VERSION 5.7 ;
  DIVIDERCHAR "/" ;
  BUSBITCHARS "[]" ;
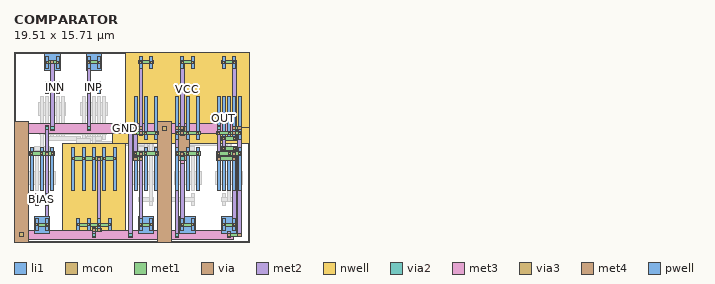
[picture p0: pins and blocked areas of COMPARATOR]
MACRO COMPARATOR
  CLASS BLOCK ;
  FOREIGN COMPARATOR ;
  ORIGIN 0.590 0.590 ;
  SIZE 19.510 BY 15.710 ;
  PIN OUT
    ANTENNADIFFAREA 0.940800 ;
    PORT
      LAYER li1 ;
        RECT 16.645 7.895 16.895 11.425 ;
        RECT 17.505 7.895 17.755 11.425 ;
        RECT 16.645 3.695 16.895 7.225 ;
        RECT 17.505 3.695 17.755 7.225 ;
      LAYER mcon ;
        RECT 16.685 7.895 16.855 8.065 ;
        RECT 17.545 7.895 17.715 8.065 ;
        RECT 16.685 7.055 16.855 7.225 ;
        RECT 17.545 7.055 17.715 7.225 ;
      LAYER met1 ;
        RECT 16.600 7.840 17.800 8.120 ;
        RECT 16.600 7.000 17.800 7.280 ;
      LAYER via ;
        RECT 16.640 7.850 16.900 8.110 ;
        RECT 16.640 7.010 16.900 7.270 ;
      LAYER met2 ;
        RECT 16.630 6.980 16.910 8.140 ;
    END
  END OUT
  PIN VCC
    ANTENNADIFFAREA 5.096000 ;
    PORT
      LAYER nwell ;
        RECT 8.600 8.840 18.920 15.120 ;
        RECT 7.550 7.560 18.920 8.840 ;
        RECT 3.440 0.000 8.600 7.560 ;
      LAYER li1 ;
        RECT 9.765 13.775 10.015 14.785 ;
        RECT 10.625 13.775 10.875 14.785 ;
        RECT 13.205 13.775 13.455 14.785 ;
        RECT 14.065 13.775 14.315 14.785 ;
        RECT 16.645 13.775 16.895 14.785 ;
        RECT 17.505 13.775 17.755 14.785 ;
        RECT 9.335 7.895 9.585 11.425 ;
        RECT 10.195 7.895 10.445 11.425 ;
        RECT 11.055 7.895 11.305 11.425 ;
        RECT 12.775 7.895 13.025 11.425 ;
        RECT 13.635 7.895 13.885 11.425 ;
        RECT 14.495 7.895 14.745 11.425 ;
        RECT 16.215 7.895 16.465 11.425 ;
        RECT 17.075 7.895 17.325 11.425 ;
        RECT 17.935 7.895 18.185 11.425 ;
        RECT 4.175 3.695 4.425 7.225 ;
        RECT 5.035 3.695 5.285 7.225 ;
        RECT 5.895 3.695 6.145 7.225 ;
        RECT 6.755 3.695 7.005 7.225 ;
        RECT 7.615 3.695 7.865 7.225 ;
        RECT 4.605 0.335 4.855 1.345 ;
        RECT 5.465 0.335 5.715 1.345 ;
        RECT 6.325 0.335 6.575 1.345 ;
        RECT 7.185 0.335 7.435 1.345 ;
      LAYER mcon ;
        RECT 9.805 14.195 9.975 14.365 ;
        RECT 10.665 14.195 10.835 14.365 ;
        RECT 13.245 14.195 13.415 14.365 ;
        RECT 14.105 14.195 14.275 14.365 ;
        RECT 16.685 14.195 16.855 14.365 ;
        RECT 17.545 14.195 17.715 14.365 ;
        RECT 9.375 8.315 9.545 8.485 ;
        RECT 10.235 8.315 10.405 8.485 ;
        RECT 11.095 8.315 11.265 8.485 ;
        RECT 12.815 8.315 12.985 8.485 ;
        RECT 13.675 8.315 13.845 8.485 ;
        RECT 14.535 8.315 14.705 8.485 ;
        RECT 16.255 8.315 16.425 8.485 ;
        RECT 17.115 8.315 17.285 8.485 ;
        RECT 17.975 8.315 18.145 8.485 ;
        RECT 4.215 6.215 4.385 6.385 ;
        RECT 5.075 6.215 5.245 6.385 ;
        RECT 5.935 6.215 6.105 6.385 ;
        RECT 6.795 6.215 6.965 6.385 ;
        RECT 7.655 6.215 7.825 6.385 ;
        RECT 4.645 0.755 4.815 0.925 ;
        RECT 5.505 0.755 5.675 0.925 ;
        RECT 6.365 0.755 6.535 0.925 ;
        RECT 7.225 0.755 7.395 0.925 ;
      LAYER met1 ;
        RECT 9.720 14.140 10.920 14.420 ;
        RECT 13.160 14.140 14.360 14.420 ;
        RECT 16.600 14.140 17.800 14.420 ;
        RECT 8.870 8.680 10.050 8.960 ;
        RECT 12.740 8.680 13.490 8.960 ;
        RECT 17.470 8.680 18.220 8.960 ;
        RECT 9.290 8.260 11.350 8.540 ;
        RECT 12.730 8.260 14.790 8.540 ;
        RECT 16.170 8.260 18.230 8.540 ;
        RECT 4.130 6.160 7.910 6.440 ;
        RECT 4.560 0.700 7.480 0.980 ;
        RECT 5.860 0.280 6.610 0.560 ;
        RECT 17.040 -0.140 18.220 0.140 ;
      LAYER via ;
        RECT 9.760 14.150 10.020 14.410 ;
        RECT 13.200 14.150 13.460 14.410 ;
        RECT 17.500 14.150 17.760 14.410 ;
        RECT 8.900 8.690 9.160 8.950 ;
        RECT 9.760 8.690 10.020 8.950 ;
        RECT 12.770 8.690 13.030 8.950 ;
        RECT 13.200 8.690 13.460 8.950 ;
        RECT 17.500 8.690 17.760 8.950 ;
        RECT 17.930 8.690 18.190 8.950 ;
        RECT 9.760 8.270 10.020 8.530 ;
        RECT 13.200 8.270 13.460 8.530 ;
        RECT 17.500 8.270 17.760 8.530 ;
        RECT 6.320 6.170 6.580 6.430 ;
        RECT 6.320 0.710 6.580 0.970 ;
        RECT 5.890 0.290 6.150 0.550 ;
        RECT 6.320 0.290 6.580 0.550 ;
        RECT 17.070 -0.130 17.330 0.130 ;
        RECT 17.930 -0.130 18.190 0.130 ;
      LAYER met2 ;
        RECT 5.880 -0.185 6.160 0.580 ;
        RECT 6.310 0.260 6.590 6.460 ;
        RECT 8.890 -0.185 9.170 8.980 ;
        RECT 9.750 8.240 10.030 14.440 ;
        RECT 12.760 -0.185 13.040 8.980 ;
        RECT 13.190 8.240 13.470 14.440 ;
        RECT 17.490 8.240 17.770 14.440 ;
        RECT 17.060 -0.185 17.340 0.240 ;
        RECT 17.920 -0.160 18.200 8.980 ;
      LAYER via2 ;
        RECT 5.880 -0.140 6.160 0.140 ;
        RECT 8.890 -0.140 9.170 0.140 ;
        RECT 12.760 -0.140 13.040 0.140 ;
        RECT 17.060 -0.140 17.340 0.140 ;
      LAYER met3 ;
        RECT -0.400 -0.400 17.600 0.400 ;
      LAYER via3 ;
        RECT -0.160 -0.160 0.160 0.160 ;
      LAYER met4 ;
        RECT -0.590 -0.590 0.590 9.410 ;
    END
  END VCC
  PIN GND
    ANTENNADIFFAREA 5.006400 ;
    PORT
      LAYER pwell ;
        RECT 1.935 13.590 3.225 14.970 ;
        RECT 5.375 13.590 6.665 14.970 ;
        RECT 1.075 0.150 2.365 1.530 ;
        RECT 9.675 0.150 10.965 1.530 ;
        RECT 13.115 0.150 14.405 1.530 ;
        RECT 16.555 0.150 17.845 1.530 ;
      LAYER li1 ;
        RECT 2.025 13.775 2.275 14.785 ;
        RECT 2.885 13.775 3.135 14.785 ;
        RECT 5.465 13.775 5.715 14.785 ;
        RECT 6.325 13.775 6.575 14.785 ;
        RECT 0.735 3.695 0.985 7.225 ;
        RECT 1.595 3.695 1.845 7.225 ;
        RECT 2.455 3.695 2.705 7.225 ;
        RECT 9.335 3.695 9.585 7.225 ;
        RECT 10.195 3.695 10.445 7.225 ;
        RECT 11.055 3.695 11.305 7.225 ;
        RECT 12.775 3.695 13.025 7.225 ;
        RECT 13.635 3.695 13.885 7.225 ;
        RECT 14.495 3.695 14.745 7.225 ;
        RECT 16.215 3.695 16.465 7.225 ;
        RECT 17.075 3.695 17.325 7.225 ;
        RECT 17.935 3.695 18.185 7.225 ;
        RECT 1.165 0.335 1.415 1.345 ;
        RECT 2.025 0.335 2.275 1.345 ;
        RECT 9.765 0.335 10.015 1.345 ;
        RECT 10.625 0.335 10.875 1.345 ;
        RECT 13.205 0.335 13.455 1.345 ;
        RECT 14.065 0.335 14.315 1.345 ;
        RECT 16.645 0.335 16.895 1.345 ;
        RECT 17.505 0.335 17.755 1.345 ;
      LAYER mcon ;
        RECT 2.065 14.195 2.235 14.365 ;
        RECT 2.925 14.195 3.095 14.365 ;
        RECT 5.505 14.195 5.675 14.365 ;
        RECT 6.365 14.195 6.535 14.365 ;
        RECT 0.775 6.635 0.945 6.805 ;
        RECT 1.635 6.635 1.805 6.805 ;
        RECT 2.495 6.635 2.665 6.805 ;
        RECT 9.375 6.635 9.545 6.805 ;
        RECT 10.235 6.635 10.405 6.805 ;
        RECT 11.095 6.635 11.265 6.805 ;
        RECT 12.815 6.635 12.985 6.805 ;
        RECT 13.675 6.635 13.845 6.805 ;
        RECT 14.535 6.635 14.705 6.805 ;
        RECT 16.255 6.635 16.425 6.805 ;
        RECT 17.115 6.635 17.285 6.805 ;
        RECT 17.975 6.635 18.145 6.805 ;
        RECT 1.205 0.755 1.375 0.925 ;
        RECT 2.065 0.755 2.235 0.925 ;
        RECT 9.805 0.755 9.975 0.925 ;
        RECT 10.665 0.755 10.835 0.925 ;
        RECT 13.245 0.755 13.415 0.925 ;
        RECT 14.105 0.755 14.275 0.925 ;
        RECT 16.685 0.755 16.855 0.925 ;
        RECT 17.545 0.755 17.715 0.925 ;
      LAYER met1 ;
        RECT 1.980 14.140 3.180 14.420 ;
        RECT 5.420 14.140 6.620 14.420 ;
        RECT 0.690 6.580 2.750 6.860 ;
        RECT 9.290 6.580 11.350 6.860 ;
        RECT 12.730 6.580 14.790 6.860 ;
        RECT 16.170 6.580 18.230 6.860 ;
        RECT 9.300 6.160 10.050 6.440 ;
        RECT 16.180 6.160 17.790 6.440 ;
        RECT 1.120 0.700 2.320 0.980 ;
        RECT 9.720 0.700 10.920 0.980 ;
        RECT 13.160 0.700 14.360 0.980 ;
        RECT 16.600 0.700 17.800 0.980 ;
      LAYER via ;
        RECT 2.450 14.150 2.710 14.410 ;
        RECT 5.460 14.150 5.720 14.410 ;
        RECT 2.020 6.590 2.280 6.850 ;
        RECT 9.760 6.590 10.020 6.850 ;
        RECT 13.200 6.590 13.460 6.850 ;
        RECT 17.500 6.590 17.760 6.850 ;
        RECT 9.330 6.170 9.590 6.430 ;
        RECT 9.760 6.170 10.020 6.430 ;
        RECT 16.210 6.170 16.470 6.430 ;
        RECT 17.500 6.170 17.760 6.430 ;
        RECT 2.020 0.710 2.280 0.970 ;
        RECT 9.760 0.710 10.020 0.970 ;
        RECT 13.200 0.710 13.460 0.970 ;
        RECT 17.500 0.710 17.760 0.970 ;
      LAYER met2 ;
        RECT 2.010 0.680 2.290 9.005 ;
        RECT 2.440 8.635 2.720 14.440 ;
        RECT 5.450 8.635 5.730 14.440 ;
        RECT 9.320 6.140 9.600 9.005 ;
        RECT 9.750 0.680 10.030 6.880 ;
        RECT 13.190 0.680 13.470 6.880 ;
        RECT 16.200 6.140 16.480 9.005 ;
        RECT 17.490 0.680 17.770 6.880 ;
      LAYER via2 ;
        RECT 2.010 8.680 2.290 8.960 ;
        RECT 2.440 8.680 2.720 8.960 ;
        RECT 5.450 8.680 5.730 8.960 ;
        RECT 9.320 8.680 9.600 8.960 ;
        RECT 16.200 8.680 16.480 8.960 ;
        RECT 13.190 6.160 13.470 6.440 ;
      LAYER met3 ;
        RECT -0.400 8.420 17.600 9.220 ;
        RECT 13.155 5.900 13.495 6.700 ;
      LAYER via3 ;
        RECT 11.680 8.660 12.000 8.980 ;
        RECT 13.160 8.660 13.480 8.980 ;
        RECT 13.160 6.140 13.480 6.460 ;
      LAYER met4 ;
        RECT 11.250 -0.590 12.430 9.410 ;
        RECT 12.730 6.135 13.910 8.985 ;
    END
  END GND
  PIN INP
    ANTENNAGATEAREA 0.504000 ;
    PORT
      LAYER li1 ;
        RECT 5.465 11.675 5.715 12.685 ;
        RECT 6.325 11.675 6.575 12.685 ;
      LAYER mcon ;
        RECT 5.505 12.095 5.675 12.265 ;
        RECT 6.365 12.095 6.535 12.265 ;
      LAYER met1 ;
        RECT 5.420 12.040 6.620 12.320 ;
    END
  END INP
  PIN INN
    ANTENNAGATEAREA 0.504000 ;
    PORT
      LAYER li1 ;
        RECT 2.025 11.675 2.275 12.685 ;
        RECT 2.885 11.675 3.135 12.685 ;
      LAYER mcon ;
        RECT 2.065 12.095 2.235 12.265 ;
        RECT 2.925 12.095 3.095 12.265 ;
      LAYER met1 ;
        RECT 1.980 12.040 3.580 12.320 ;
    END
  END INN
  PIN BIAS
    ANTENNAGATEAREA 0.504000 ;
    PORT
      LAYER li1 ;
        RECT 1.165 2.435 1.415 3.445 ;
        RECT 2.025 2.435 2.275 3.445 ;
      LAYER mcon ;
        RECT 1.205 2.855 1.375 3.025 ;
        RECT 2.065 2.855 2.235 3.025 ;
      LAYER met1 ;
        RECT 1.120 2.800 2.320 3.080 ;
    END
  END BIAS
  OBS
      LAYER pwell ;
        RECT 1.465 9.845 3.695 10.945 ;
        RECT 4.905 9.845 7.135 10.945 ;
        RECT 0.605 4.175 2.835 5.275 ;
        RECT 9.205 4.175 11.435 5.275 ;
        RECT 12.645 4.175 14.875 5.275 ;
        RECT 16.085 4.175 18.315 5.275 ;
      LAYER li1 ;
        RECT 9.765 11.675 10.015 12.685 ;
        RECT 10.625 11.675 10.875 12.685 ;
        RECT 1.595 7.895 1.845 11.425 ;
        RECT 2.025 7.895 2.275 11.425 ;
        RECT 2.455 7.895 2.705 11.425 ;
        RECT 2.885 7.895 3.135 11.425 ;
        RECT 3.315 7.895 3.565 11.425 ;
        RECT 5.035 7.895 5.285 11.425 ;
        RECT 5.465 7.895 5.715 11.425 ;
        RECT 5.895 7.895 6.145 11.425 ;
        RECT 6.325 7.895 6.575 11.425 ;
        RECT 6.755 7.895 7.005 11.425 ;
        RECT 9.765 7.895 10.015 11.425 ;
        RECT 10.625 7.895 10.875 11.425 ;
        RECT 1.165 3.695 1.415 7.225 ;
        RECT 2.025 3.695 2.275 7.225 ;
        RECT 4.605 3.695 4.855 7.225 ;
        RECT 5.465 3.695 5.715 7.225 ;
        RECT 6.325 3.695 6.575 7.225 ;
        RECT 7.185 3.695 7.435 7.225 ;
        RECT 9.765 3.695 10.015 7.225 ;
        RECT 10.625 3.695 10.875 7.225 ;
        RECT 4.605 2.435 4.855 3.445 ;
        RECT 5.465 2.435 5.715 3.445 ;
        RECT 6.325 2.435 6.575 3.445 ;
        RECT 7.185 2.435 7.435 3.445 ;
        RECT 9.765 2.435 10.015 3.445 ;
        RECT 10.625 2.435 10.875 3.445 ;
        RECT 11.485 2.855 11.735 12.265 ;
        RECT 13.205 11.675 13.455 12.685 ;
        RECT 14.065 11.675 14.315 12.685 ;
        RECT 16.645 11.675 16.895 12.685 ;
        RECT 17.505 11.675 17.755 12.685 ;
        RECT 13.205 7.895 13.455 11.425 ;
        RECT 14.065 7.895 14.315 11.425 ;
        RECT 13.205 3.695 13.455 7.225 ;
        RECT 14.065 3.695 14.315 7.225 ;
        RECT 13.205 2.435 13.455 3.445 ;
        RECT 14.065 2.435 14.315 3.445 ;
        RECT 16.645 2.435 16.895 3.445 ;
        RECT 17.505 2.435 17.755 3.445 ;
      LAYER mcon ;
        RECT 9.805 12.095 9.975 12.265 ;
        RECT 10.665 12.095 10.835 12.265 ;
        RECT 11.525 12.095 11.695 12.265 ;
        RECT 1.635 8.315 1.805 8.485 ;
        RECT 2.065 7.895 2.235 8.065 ;
        RECT 2.495 8.315 2.665 8.485 ;
        RECT 2.925 7.895 3.095 8.065 ;
        RECT 3.355 8.315 3.525 8.485 ;
        RECT 5.075 8.315 5.245 8.485 ;
        RECT 5.505 7.895 5.675 8.065 ;
        RECT 5.935 8.315 6.105 8.485 ;
        RECT 6.365 7.895 6.535 8.065 ;
        RECT 6.795 8.315 6.965 8.485 ;
        RECT 9.805 7.895 9.975 8.065 ;
        RECT 10.665 7.895 10.835 8.065 ;
        RECT 13.245 12.095 13.415 12.265 ;
        RECT 14.105 12.095 14.275 12.265 ;
        RECT 16.685 12.095 16.855 12.265 ;
        RECT 17.545 12.095 17.715 12.265 ;
        RECT 13.245 7.895 13.415 8.065 ;
        RECT 14.105 7.895 14.275 8.065 ;
        RECT 1.205 7.055 1.375 7.225 ;
        RECT 2.065 7.055 2.235 7.225 ;
        RECT 4.645 7.055 4.815 7.225 ;
        RECT 5.505 6.635 5.675 6.805 ;
        RECT 6.365 6.635 6.535 6.805 ;
        RECT 7.225 7.055 7.395 7.225 ;
        RECT 9.805 7.055 9.975 7.225 ;
        RECT 10.665 7.055 10.835 7.225 ;
        RECT 11.525 7.055 11.695 7.225 ;
        RECT 4.645 2.855 4.815 3.025 ;
        RECT 5.505 2.855 5.675 3.025 ;
        RECT 6.365 2.855 6.535 3.025 ;
        RECT 7.225 2.855 7.395 3.025 ;
        RECT 9.805 2.855 9.975 3.025 ;
        RECT 10.665 2.855 10.835 3.025 ;
        RECT 13.245 7.055 13.415 7.225 ;
        RECT 14.105 7.055 14.275 7.225 ;
        RECT 11.525 2.855 11.695 3.025 ;
        RECT 13.245 2.855 13.415 3.025 ;
        RECT 14.105 2.855 14.275 3.025 ;
        RECT 16.685 2.855 16.855 3.025 ;
        RECT 17.545 2.855 17.715 3.025 ;
      LAYER met1 ;
        RECT 9.720 12.040 10.920 12.320 ;
        RECT 11.440 12.040 14.360 12.320 ;
        RECT 16.600 12.040 17.800 12.320 ;
        RECT 1.550 8.260 7.050 8.540 ;
        RECT 1.980 7.840 4.890 8.120 ;
        RECT 5.420 7.840 6.620 8.120 ;
        RECT 9.720 7.840 10.920 8.120 ;
        RECT 13.160 7.840 14.360 8.120 ;
        RECT 5.860 7.420 10.910 7.700 ;
        RECT 13.600 7.420 17.360 7.700 ;
        RECT 1.120 7.000 2.320 7.280 ;
        RECT 4.560 7.000 7.480 7.280 ;
        RECT 9.720 7.000 11.780 7.280 ;
        RECT 13.160 7.000 14.360 7.280 ;
        RECT 5.420 6.580 6.620 6.860 ;
        RECT 4.560 2.800 7.480 3.080 ;
        RECT 9.720 2.800 10.920 3.080 ;
        RECT 11.440 2.800 14.360 3.080 ;
        RECT 16.600 2.800 17.800 3.080 ;
      LAYER via ;
        RECT 10.620 12.050 10.880 12.310 ;
        RECT 17.070 12.050 17.330 12.310 ;
        RECT 1.590 8.270 1.850 8.530 ;
        RECT 4.600 7.850 4.860 8.110 ;
        RECT 5.890 7.850 6.150 8.110 ;
        RECT 10.190 7.850 10.450 8.110 ;
        RECT 13.630 7.850 13.890 8.110 ;
        RECT 5.890 7.430 6.150 7.690 ;
        RECT 10.620 7.430 10.880 7.690 ;
        RECT 13.630 7.430 13.890 7.690 ;
        RECT 17.070 7.430 17.330 7.690 ;
        RECT 1.590 7.010 1.850 7.270 ;
        RECT 5.460 7.010 5.720 7.270 ;
        RECT 10.190 7.010 10.450 7.270 ;
        RECT 13.630 7.010 13.890 7.270 ;
        RECT 5.890 6.590 6.150 6.850 ;
        RECT 5.460 2.810 5.720 3.070 ;
        RECT 10.620 2.810 10.880 3.070 ;
        RECT 17.070 2.810 17.330 3.070 ;
      LAYER met2 ;
        RECT 1.580 6.980 1.860 8.560 ;
        RECT 4.590 7.375 4.870 8.140 ;
        RECT 5.450 2.780 5.730 7.745 ;
        RECT 5.880 6.560 6.160 8.140 ;
        RECT 10.180 6.980 10.460 8.140 ;
        RECT 10.610 2.780 10.890 12.340 ;
        RECT 13.620 6.980 13.900 8.140 ;
        RECT 17.060 2.780 17.340 12.340 ;
      LAYER via2 ;
        RECT 4.590 7.420 4.870 7.700 ;
        RECT 5.450 7.420 5.730 7.700 ;
      LAYER met3 ;
        RECT 4.565 7.160 5.755 7.960 ;
  END
END COMPARATOR
END LIBRARY

